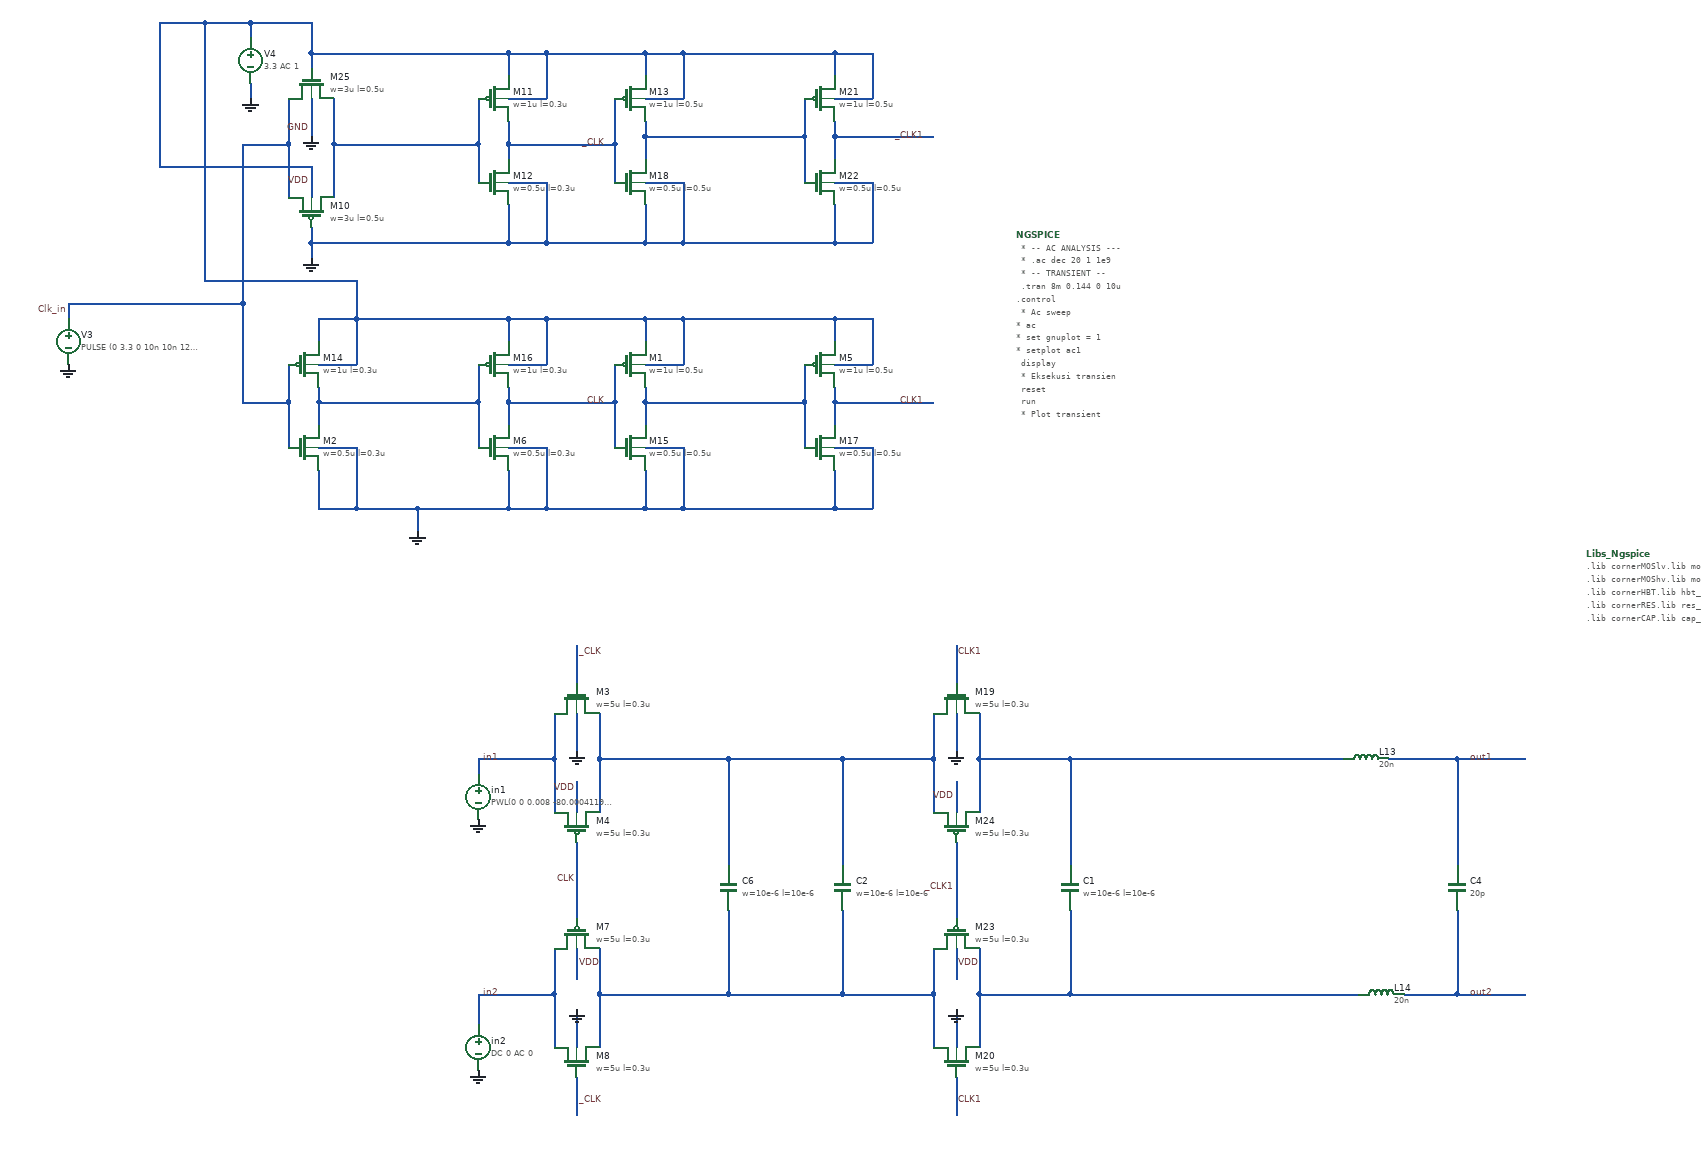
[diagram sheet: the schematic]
v {xschem version=3.4.6 file_version=1.2}
G {}
K {}
V {}
S {}
E {}
N 540 -1400 540 -1330 {lab=Clk_in}
N 600 -1400 600 -1330 {lab=#net1}
N 570 -1460 570 -1410 {lab=GND}
N 570 -1370 570 -1330 {lab=VDD}
N 570 -1270 570 -1250 {lab=GND}
N 570 -1520 570 -1500 {lab=VDD}
N 480 -1400 480 -1190 {lab=Clk_in}
N 480 -1400 540 -1400 {lab=Clk_in}
N 790 -1400 790 -1350 {lab=#net1}
N 600 -1400 790 -1400 {lab=#net1}
N 830 -1400 830 -1370 {lab=_CLK}
N 830 -1400 970 -1400 {lab=_CLK}
N 570 -1520 830 -1520 {lab=VDD}
N 830 -1520 830 -1490 {lab=VDD}
N 570 -1270 830 -1270 {lab=GND}
N 830 -1320 830 -1270 {lab=GND}
N 830 -1460 880 -1460 {lab=VDD}
N 880 -1520 880 -1460 {lab=VDD}
N 830 -1520 880 -1520 {lab=VDD}
N 830 -1350 880 -1350 {lab=GND}
N 880 -1350 880 -1270 {lab=GND}
N 830 -1270 880 -1270 {lab=GND}
N 540 -1060 540 -1000 {lab=Clk_in}
N 580 -1060 580 -1020 {lab=#net2}
N 580 -1170 580 -1140 {lab=VDD}
N 580 -970 580 -920 {lab=GND}
N 580 -1110 630 -1110 {lab=VDD}
N 630 -1170 630 -1110 {lab=VDD}
N 580 -1170 630 -1170 {lab=VDD}
N 580 -1000 630 -1000 {lab=GND}
N 630 -1000 630 -920 {lab=GND}
N 580 -920 630 -920 {lab=GND}
N 480 -1190 480 -1060 {lab=Clk_in}
N 480 -1060 540 -1060 {lab=Clk_in}
N 790 -1060 790 -1000 {lab=#net2}
N 830 -1060 830 -1020 {lab=CLK}
N 830 -1170 830 -1140 {lab=VDD}
N 830 -970 830 -920 {lab=GND}
N 830 -1110 880 -1110 {lab=VDD}
N 880 -1170 880 -1110 {lab=VDD}
N 830 -1170 880 -1170 {lab=VDD}
N 830 -1000 880 -1000 {lab=GND}
N 880 -1000 880 -920 {lab=GND}
N 830 -920 880 -920 {lab=GND}
N 580 -1060 790 -1060 {lab=#net2}
N 830 -1060 970 -1060 {lab=CLK}
N 630 -1170 830 -1170 {lab=VDD}
N 710 -920 830 -920 {lab=GND}
N 250 -1190 250 -1170 {lab=Clk_in}
N 490 -1560 570 -1560 {lab=VDD}
N 490 -1480 490 -1460 {lab=GND}
N 630 -1220 630 -1170 {lab=VDD}
N 430 -1220 630 -1220 {lab=VDD}
N 430 -1560 430 -1220 {lab=VDD}
N 430 -1560 490 -1560 {lab=VDD}
N 490 -1560 490 -1540 {lab=VDD}
N 370 -1370 570 -1370 {lab=VDD}
N 370 -1560 370 -1370 {lab=VDD}
N 370 -1560 430 -1560 {lab=VDD}
N 710 -920 710 -890 {lab=GND}
N 2080 -590 2170 -590 {lab=out1}
N 970 -1060 970 -1000 {lab=CLK}
N 1010 -1060 1010 -1020 {lab=#net3}
N 1010 -1170 1010 -1140 {lab=VDD}
N 1010 -970 1010 -920 {lab=GND}
N 1010 -1110 1060 -1110 {lab=VDD}
N 1060 -1170 1060 -1110 {lab=VDD}
N 1010 -1170 1060 -1170 {lab=VDD}
N 1010 -1000 1060 -1000 {lab=GND}
N 1060 -1000 1060 -920 {lab=GND}
N 1010 -920 1060 -920 {lab=GND}
N 1220 -1060 1220 -1000 {lab=#net3}
N 1260 -1060 1260 -1020 {lab=CLK1}
N 1260 -1170 1260 -1140 {lab=VDD}
N 1260 -970 1260 -920 {lab=GND}
N 1260 -1110 1310 -1110 {lab=VDD}
N 1310 -1170 1310 -1110 {lab=VDD}
N 1260 -1170 1310 -1170 {lab=VDD}
N 1260 -1000 1310 -1000 {lab=GND}
N 1310 -1000 1310 -920 {lab=GND}
N 1260 -920 1310 -920 {lab=GND}
N 1010 -1060 1220 -1060 {lab=#net3}
N 1060 -1170 1260 -1170 {lab=VDD}
N 1060 -920 1260 -920 {lab=GND}
N 1260 -1060 1390 -1060 {lab=CLK1}
N 970 -1400 970 -1350 {lab=_CLK}
N 1010 -1410 1010 -1370 {lab=#net4}
N 1010 -1520 1010 -1490 {lab=VDD}
N 1010 -1320 1010 -1270 {lab=GND}
N 1010 -1460 1060 -1460 {lab=VDD}
N 1060 -1520 1060 -1460 {lab=VDD}
N 1010 -1520 1060 -1520 {lab=VDD}
N 1010 -1350 1060 -1350 {lab=GND}
N 1060 -1350 1060 -1270 {lab=GND}
N 1220 -1410 1220 -1350 {lab=#net4}
N 1260 -1410 1260 -1370 {lab=_CLK1}
N 1260 -1520 1260 -1490 {lab=VDD}
N 1260 -1320 1260 -1270 {lab=GND}
N 1260 -1460 1310 -1460 {lab=VDD}
N 1310 -1520 1310 -1460 {lab=VDD}
N 1260 -1520 1310 -1520 {lab=VDD}
N 1260 -1350 1310 -1350 {lab=GND}
N 1310 -1350 1310 -1270 {lab=GND}
N 1260 -1270 1310 -1270 {lab=GND}
N 1010 -1410 1220 -1410 {lab=#net4}
N 1060 -1520 1260 -1520 {lab=VDD}
N 1060 -1270 1260 -1270 {lab=GND}
N 1260 -1410 1390 -1410 {lab=_CLK1}
N 880 -1520 1010 -1520 {lab=VDD}
N 1010 -1270 1060 -1270 {lab=GND}
N 880 -1170 1010 -1170 {lab=VDD}
N 880 -920 1010 -920 {lab=GND}
N 250 -1190 480 -1190 {lab=Clk_in}
N 2080 -590 2080 -450 {lab=out1}
N 2080 -390 2080 -280 {lab=out2}
N 2080 -280 2170 -280 {lab=out2}
N 1990 -590 2080 -590 {lab=out1}
N 2010 -280 2080 -280 {lab=out2}
N 540 -1460 540 -1400 {lab=Clk_in}
N 600 -1460 600 -1400 {lab=#net1}
N 790 -1460 790 -1400 {lab=#net1}
N 830 -1430 830 -1400 {lab=_CLK}
N 970 -1460 970 -1400 {lab=_CLK}
N 570 -1560 570 -1520 {lab=VDD}
N 570 -1290 570 -1270 {lab=GND}
N 540 -1110 540 -1060 {lab=Clk_in}
N 580 -1080 580 -1060 {lab=#net2}
N 790 -1110 790 -1060 {lab=#net2}
N 830 -1080 830 -1060 {lab=CLK}
N 970 -1110 970 -1060 {lab=CLK}
N 630 -920 710 -920 {lab=GND}
N 1010 -1080 1010 -1060 {lab=#net3}
N 1220 -1110 1220 -1060 {lab=#net3}
N 1260 -1080 1260 -1060 {lab=CLK1}
N 880 -1270 1010 -1270 {lab=GND}
N 1010 -1430 1010 -1410 {lab=#net4}
N 1220 -1460 1220 -1410 {lab=#net4}
N 1260 -1430 1260 -1410 {lab=_CLK1}
N 790 -590 890 -590 {lab=in1}
N 890 -590 890 -520 {lab=in1}
N 950 -590 950 -520 {lab=#net5}
N 920 -650 920 -600 {lab=GND}
N 920 -560 920 -520 {lab=VDD}
N 920 -740 920 -690 {lab=_CLK}
N 920 -480 920 -380 {lab=CLK}
N 950 -590 1120 -590 {lab=#net5}
N 950 -280 950 -210 {lab=#net6}
N 890 -280 890 -210 {lab=in2}
N 920 -260 920 -210 {lab=GND}
N 920 -340 920 -300 {lab=VDD}
N 920 -170 920 -120 {lab=_CLK}
N 790 -280 890 -280 {lab=in2}
N 950 -280 1120 -280 {lab=#net6}
N 1120 -280 1270 -280 {lab=#net6}
N 1120 -590 1270 -590 {lab=#net5}
N 1390 -590 1390 -520 {lab=#net5}
N 1450 -590 1450 -520 {lab=#net7}
N 1420 -650 1420 -600 {lab=GND}
N 1420 -560 1420 -520 {lab=VDD}
N 1420 -740 1420 -690 {lab=CLK1}
N 1420 -480 1420 -380 {lab=_CLK1}
N 1450 -590 1570 -590 {lab=#net7}
N 1450 -280 1450 -210 {lab=#net8}
N 1390 -280 1390 -210 {lab=#net6}
N 1420 -260 1420 -210 {lab=GND}
N 1420 -340 1420 -300 {lab=VDD}
N 1420 -170 1420 -120 {lab=CLK1}
N 1270 -590 1390 -590 {lab=#net5}
N 1270 -280 1390 -280 {lab=#net6}
N 1450 -280 1570 -280 {lab=#net8}
N 1570 -590 1570 -450 {lab=#net7}
N 1120 -590 1120 -450 {lab=#net5}
N 1270 -590 1270 -450 {lab=#net5}
N 1120 -390 1120 -280 {lab=#net6}
N 1270 -390 1270 -280 {lab=#net6}
N 1570 -390 1570 -280 {lab=#net8}
N 1570 -280 1950 -280 {lab=#net8}
N 1570 -590 1930 -590 {lab=#net7}
N 890 -650 890 -590 {lab=in1}
N 950 -650 950 -590 {lab=#net5}
N 890 -340 890 -280 {lab=in2}
N 950 -340 950 -280 {lab=#net6}
N 1450 -650 1450 -590 {lab=#net7}
N 1390 -650 1390 -590 {lab=#net5}
N 1390 -340 1390 -280 {lab=#net6}
N 1450 -340 1450 -280 {lab=#net8}
N 790 -590 790 -570 {lab=in1}
N 790 -280 790 -240 {lab=in2}
C {lab_wire.sym} 570 -1420 0 0 {name=p20 sig_type=std_logic lab=GND}
C {lab_wire.sym} 570 -1350 0 0 {name=p21 sig_type=std_logic lab=VDD}
C {lab_wire.sym} 960 -1060 0 0 {name=p24 sig_type=std_logic lab=CLK}
C {lab_wire.sym} 960 -1400 0 0 {name=p25 sig_type=std_logic lab=_CLK}
C {vsource.sym} 250 -1140 0 0 {name=V3 value="PULSE (0 3.3 0 10n 10n 125n 250n) AC 0" savecurrent=false}
C {gnd.sym} 250 -1110 0 0 {name=l2 lab=GND}
C {lab_wire.sym} 250 -1180 0 0 {name=p23 sig_type=std_logic lab=Clk_in}
C {noconn.sym} 970 -1400 2 0 {name=l3}
C {noconn.sym} 970 -1060 2 0 {name=l4}
C {vsource.sym} 490 -1510 0 0 {name=V4 value="3.3 AC 1" savecurrent=false}
C {gnd.sym} 490 -1460 0 0 {name=l6 lab=GND}
C {gnd.sym} 570 -1250 0 0 {name=l7 lab=GND}
C {gnd.sym} 570 -1410 0 0 {name=l8 lab=GND}
C {gnd.sym} 710 -890 0 0 {name=l9 lab=GND}
C {noconn.sym} 2170 -590 2 0 {name=l10}
C {noconn.sym} 2170 -280 2 0 {name=l11}
C {lab_wire.sym} 2130 -590 1 0 {name=p30 sig_type=std_logic lab=out1}
C {lab_wire.sym} 2130 -280 3 0 {name=p37 sig_type=std_logic lab=out2}
C {devices/code_shown.sym} 1500 -1280 0 0 {name=NGSPICE only_toplevel=true
value="
	* -- AC ANALYSIS ---
	* .ac dec 20 1 1e9
	* -- TRANSIENT --
	.tran 8m 0.144 0 10u
.control
	* Ac sweep
*	ac
*	set gnuplot = 1
*	setplot ac1
	display
	
	* Eksekusi transien
	reset
	run

	* Plot transient
	plot V(in1)-V(in2) 
	plot V(out1)-V(out2)
	plot db((V(out1)-V(out2))/(V(in1)-V(in2)))
	*plot ph(V(out1)-V(out2))

*a %vd([1 0 2 0]) filesrc
*.model filesrc filesource (file="CH1_2.txt" amploffset=[0 0] amplscale=[1 1]
*+ timeoffset=0 timescale=1
*+ timerelative=false amplstep=false)

*plot V(filesrc)

save all

.endc
"}
C {lab_wire.sym} 1380 -1060 0 0 {name=p2 sig_type=std_logic lab=CLK1}
C {noconn.sym} 970 -1410 2 0 {name=l5}
C {lab_wire.sym} 1380 -1410 0 0 {name=p3 sig_type=std_logic lab=_CLK1}
C {ind.sym} 1960 -590 3 0 {name=L13
m=1
value=20n
footprint=1206
device=inductor}
C {capa.sym} 2080 -420 0 0 {name=C4
m=1
value=20p
footprint=1206
device="ceramic capacitor"}
C {ind.sym} 1980 -280 3 0 {name=L14
m=1
value=20n
footprint=1206
device=inductor}
C {lab_wire.sym} 920 -320 2 0 {name=p11 sig_type=std_logic lab=VDD
nf=1
L=0.3u
m=1
W=4u}
C {lab_wire.sym} 920 -140 2 0 {name=p12 sig_type=std_logic lab=_CLK
W=4u}
C {lab_wire.sym} 1420 -540 0 0 {name=p7 sig_type=std_logic lab=VDD
nf=1
L=0.3u
m=1
W=4u}
C {lab_wire.sym} 1420 -320 2 0 {name=p14 sig_type=std_logic lab=VDD
nf=1
L=0.3u
m=1
W=4u}
C {lab_wire.sym} 1420 -140 2 0 {name=p15 sig_type=std_logic lab=CLK1
W=4u}
C {sg13g2_pr/cap_cmim.sym} 1570 -420 0 0 {name=C1
model=cap_cmim
w=10e-6
l=10e-6
m=3
spiceprefix=X}
C {sg13g2_pr/cap_cmim.sym} 1270 -420 0 0 {name=C2
model=cap_cmim
w=10e-6
l=10e-6
m=3
spiceprefix=X}
C {sg13g2_pr/cap_cmim.sym} 1120 -420 0 0 {name=C6
model=cap_cmim
w=10e-6
l=10e-6
m=3
spiceprefix=X}
C {sg13g2_pr/sg13_lv_pmos.sym} 920 -360 1 0 {name=M7
l=0.3u
w=5u
ng=3
m=1
model=sg13_lv_pmos
spiceprefix=X
}
C {sg13g2_pr/sg13_lv_nmos.sym} 920 -190 3 0 {name=M8
l=0.3u
w=5u
ng=3
m=1
model=sg13_lv_nmos
spiceprefix=X
}
C {sg13g2_pr/sg13_lv_nmos.sym} 920 -670 1 0 {name=M3
l=0.3u
w=5u
ng=3
m=1
model=sg13_lv_nmos
spiceprefix=X
}
C {sg13g2_pr/sg13_lv_pmos.sym} 920 -500 3 0 {name=M4
l=0.3u
w=5u
ng=3
m=1
model=sg13_lv_pmos
spiceprefix=X
}
C {sg13g2_pr/sg13_lv_nmos.sym} 1420 -670 1 0 {name=M19
l=0.3u
w=5u
ng=3
m=1
model=sg13_lv_nmos
spiceprefix=X
}
C {sg13g2_pr/sg13_lv_nmos.sym} 1420 -190 3 0 {name=M20
l=0.3u
w=5u
ng=3
m=1
model=sg13_lv_nmos
spiceprefix=X
}
C {sg13g2_pr/sg13_lv_pmos.sym} 1420 -360 1 0 {name=M23
l=0.3u
w=5u
ng=3
m=1
model=sg13_lv_pmos
spiceprefix=X
}
C {sg13g2_pr/sg13_lv_pmos.sym} 1420 -500 3 0 {name=M24
l=0.3u
w=5u
ng=3
m=1
model=sg13_lv_pmos
spiceprefix=X
}
C {sg13g2_pr/sg13_lv_nmos.sym} 560 -1000 0 0 {name=M2
l=0.3u
w=0.5u
ng=1
m=1
model=sg13_lv_nmos
spiceprefix=X
}
C {sg13g2_pr/sg13_lv_nmos.sym} 810 -1000 0 0 {name=M6
l=0.3u
w=0.5u
ng=1
m=1
model=sg13_lv_nmos
spiceprefix=X
}
C {sg13g2_pr/sg13_lv_nmos.sym} 990 -1000 0 0 {name=M15
l=0.5u
w=0.5u
ng=1
m=1
model=sg13_lv_nmos
spiceprefix=X
}
C {sg13g2_pr/sg13_lv_nmos.sym} 1240 -1000 0 0 {name=M17
l=0.5u
w=0.5u
ng=1
m=1
model=sg13_lv_nmos
spiceprefix=X
}
C {sg13g2_pr/sg13_lv_pmos.sym} 560 -1110 0 0 {name=M14
l=0.3u
w=1u
ng=1
m=1
model=sg13_lv_pmos
spiceprefix=X
}
C {sg13g2_pr/sg13_lv_pmos.sym} 810 -1110 0 0 {name=M16
l=0.3u
w=1u
ng=1
m=1
model=sg13_lv_pmos
spiceprefix=X
}
C {sg13g2_pr/sg13_lv_pmos.sym} 990 -1110 0 0 {name=M1
l=0.5u
w=1u
ng=2
m=1
model=sg13_lv_pmos
spiceprefix=X
}
C {sg13g2_pr/sg13_lv_pmos.sym} 1240 -1110 0 0 {name=M5
l=0.5u
w=1u
ng=2
m=1
model=sg13_lv_pmos
spiceprefix=X
}
C {sg13g2_pr/sg13_lv_pmos.sym} 810 -1460 0 0 {name=M11
l=0.3u
w=1u
ng=1
m=1
model=sg13_lv_pmos
spiceprefix=X
}
C {sg13g2_pr/sg13_lv_pmos.sym} 990 -1460 0 0 {name=M13
l=0.5u
w=1u
ng=2
m=1
model=sg13_lv_pmos
spiceprefix=X
}
C {sg13g2_pr/sg13_lv_pmos.sym} 1240 -1460 0 0 {name=M21
l=0.5u
w=1u
ng=2
m=1
model=sg13_lv_pmos
spiceprefix=X
}
C {sg13g2_pr/sg13_lv_nmos.sym} 810 -1350 0 0 {name=M12
l=0.3u
w=0.5u
ng=1
m=1
model=sg13_lv_nmos
spiceprefix=X
}
C {sg13g2_pr/sg13_lv_nmos.sym} 990 -1350 0 0 {name=M18
l=0.5u
w=0.5u
ng=1
m=1
model=sg13_lv_nmos
spiceprefix=X
}
C {sg13g2_pr/sg13_lv_nmos.sym} 1240 -1350 0 0 {name=M22
l=0.5u
w=0.5u
ng=1
m=1
model=sg13_lv_nmos
spiceprefix=X
}
C {sg13g2_pr/sg13_lv_pmos.sym} 570 -1310 3 0 {name=M10
l=0.5u
w=3u
ng=5
m=1
model=sg13_lv_pmos
spiceprefix=X
}
C {sg13g2_pr/sg13_lv_nmos.sym} 570 -1480 1 0 {name=M25
l=0.5u
w=3u
ng=5
m=1
model=sg13_lv_nmos
spiceprefix=X
}
C {vsource.sym} 790 -540 0 0 {name=in1 value="PWL(0 0 0.008 -80.00041199u 0.016 -133.086319u 0.024 85.89277649u 0.032 -94.17173767u 0.04 43.23672485u 0.048 10.87415981u 0.056 19.15146637u 0.064 13.92291355u 0.072 16.32160759u 0.08 4.195819378u 0.088 3.323663712u 0.096 8.602978706u 0.104 -7.884923935u 0.112 -14.38331318u 0.12 -10.79214478u 0.128 -8.228297234u 0.136 -7.73075819u 0.144 12.37324333u)" savecurrent=false}
C {gnd.sym} 790 -510 0 0 {name=l1 lab=GND}
C {vsource.sym} 790 -210 0 0 {name=in2 value="DC 0 AC 0" savecurrent=false}
C {gnd.sym} 790 -180 0 0 {name=l12 lab=GND}
C {lab_wire.sym} 920 -730 2 0 {name=p5 sig_type=std_logic lab=_CLK
W=4u}
C {lab_wire.sym} 1420 -730 2 0 {name=p8 sig_type=std_logic lab=CLK1
W=4u}
C {lab_wire.sym} 1420 -420 0 0 {name=p13 sig_type=std_logic lab=_CLK1}
C {lab_wire.sym} 920 -430 0 0 {name=p6 sig_type=std_logic lab=CLK}
C {simulator_commands_shown.sym} 2250 -860 0 0 {
name=Libs_Ngspice
simulator=ngspice
only_toplevel=false
value="
.lib cornerMOSlv.lib mos_tt
.lib cornerMOShv.lib mos_tt
.lib cornerHBT.lib hbt_typ
.lib cornerRES.lib res_typ
.lib cornerCAP.lib cap_typ
"
      }
C {lab_wire.sym} 920 -550 0 0 {name=p16 sig_type=std_logic lab=VDD}
C {gnd.sym} 920 -600 0 0 {name=l15 lab=GND}
C {gnd.sym} 1420 -600 0 0 {name=l16 lab=GND}
C {gnd.sym} 1420 -260 2 0 {name=l17 lab=GND}
C {gnd.sym} 920 -260 2 0 {name=l18 lab=GND}
C {lab_wire.sym} 820 -590 0 0 {name=p1 sig_type=std_logic lab=in1}
C {lab_wire.sym} 820 -280 0 0 {name=p4 sig_type=std_logic lab=in2}
